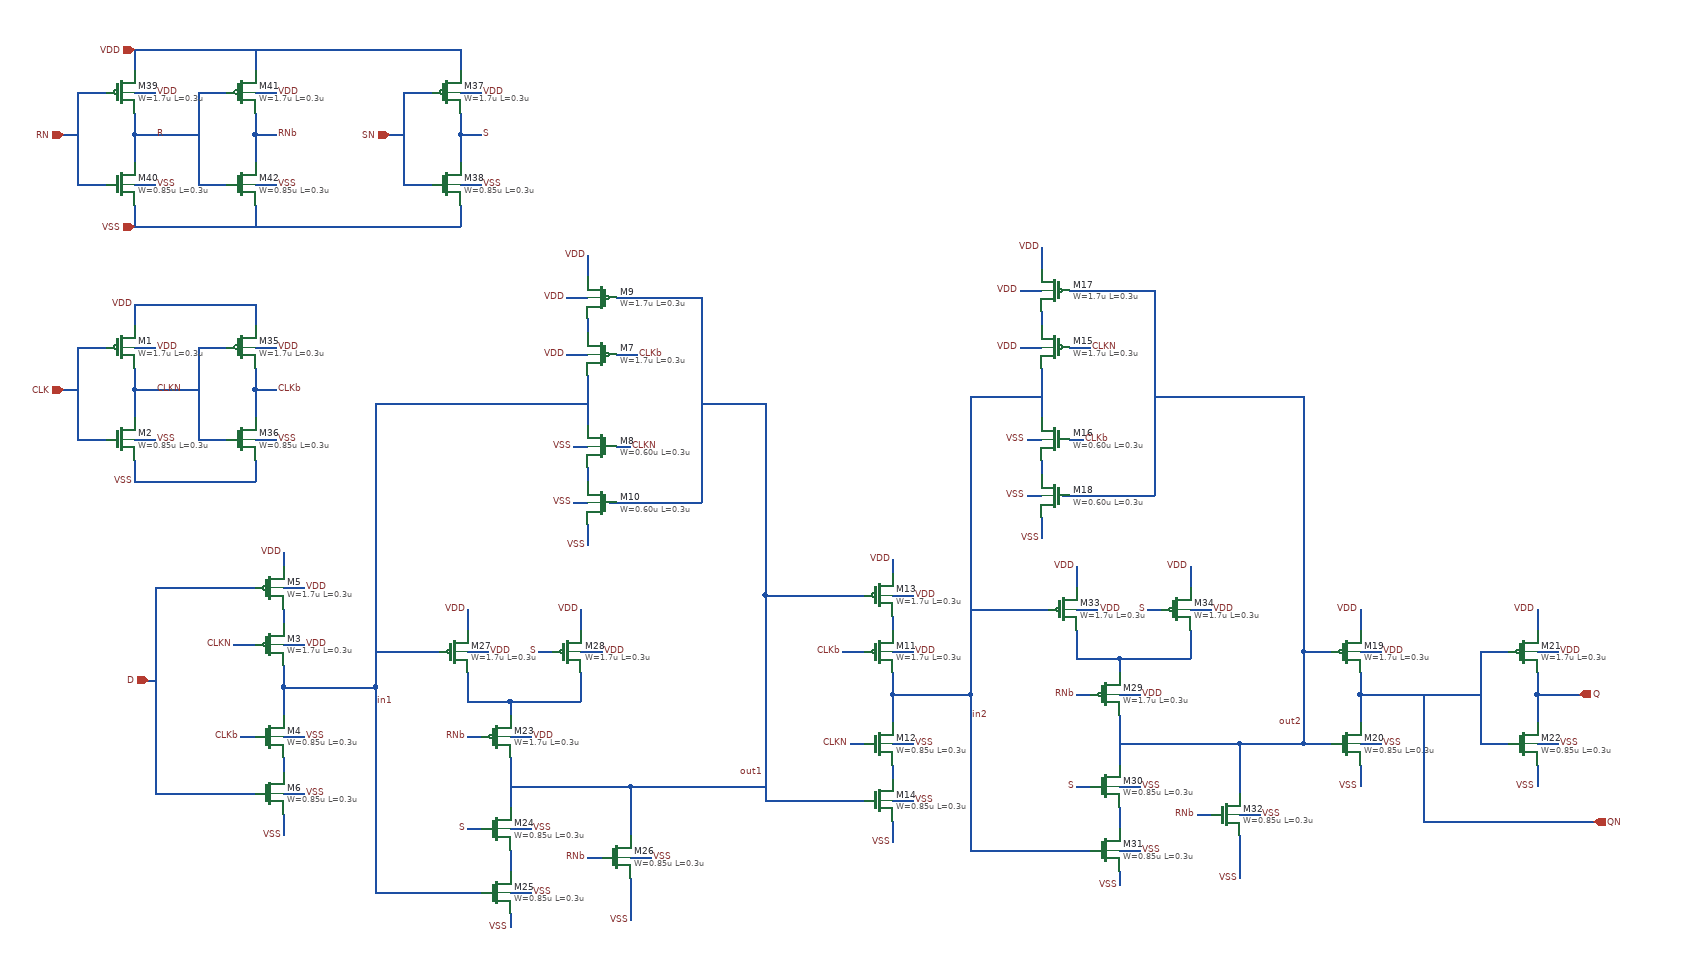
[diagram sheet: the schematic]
v {xschem version=3.4.6 file_version=1.2}
G {}
K {}
V {}
S {}
E {}
N 60 -780 60 -750 { lab=VDD}
N 60 -690 60 -660 { lab=CLKN}
N 60 -660 60 -620 { lab=CLKN}
N 60 -560 60 -530 { lab=VSS}
N 0 -720 20 -720 { lab=CLK}
N -20 -720 -20 -590 { lab=CLK}
N -40 -660 -20 -660 { lab=CLK}
N -20 -720 0 -720 { lab=CLK}
N -20 -590 20 -590 { lab=CLK}
N 60 -720 90 -720 { lab=VDD}
N 60 -590 90 -590 { lab=VSS}
N 270 -270 270 -240 { lab=in1}
N 270 -240 270 -200 { lab=in1}
N 270 -300 300 -300 { lab=VDD}
N 270 -170 300 -170 { lab=VSS}
N 210 -380 230 -380 { lab=D}
N 270 -380 300 -380 { lab=VDD}
N 270 -350 270 -330 { lab=#net1}
N 270 -60 270 -30 { lab=VSS}
N 270 -90 300 -90 { lab=VSS}
N 270 -140 270 -120 { lab=#net2}
N 270 -430 270 -400 { lab=#net3}
N 90 -90 230 -90 { lab=D}
N 90 -380 90 -90 { lab=D}
N 90 -380 210 -380 { lab=D}
N 80 -250 90 -250 { lab=D}
N 700 -470 700 -440 { lab=VSS}
N 700 -850 700 -820 { lab=#net4}
N 700 -760 700 -740 { lab=#net5}
N 700 -550 700 -530 { lab=#net6}
N 700 -680 700 -610 { lab=in1}
N 670 -790 700 -790 { lab=VDD}
N 670 -710 700 -710 { lab=VDD}
N 680 -500 700 -500 { lab=VSS}
N 680 -580 700 -580 { lab=VSS}
N 730 -500 860 -500 { lab=out1}
N 740 -790 860 -790 { lab=out1}
N 860 -790 860 -500 { lab=out1}
N 740 -710 770 -710 { lab=CLKb}
N 740 -580 760 -580 { lab=CLKN}
N 1130 -260 1130 -230 { lab=in2}
N 1130 -230 1130 -190 { lab=in2}
N 1130 -290 1160 -290 { lab=VDD}
N 1130 -160 1160 -160 { lab=VSS}
N 1130 -230 1160 -230 { lab=in2}
N 1070 -370 1090 -370 { lab=out1}
N 1130 -370 1160 -370 { lab=VDD}
N 1130 -340 1130 -320 { lab=#net7}
N 1130 -50 1130 -20 { lab=VSS}
N 1130 -80 1160 -80 { lab=VSS}
N 1130 -130 1130 -110 { lab=#net8}
N 1130 -420 1130 -390 { lab=#net9}
N 950 -80 1090 -80 { lab=out1}
N 950 -370 1070 -370 { lab=out1}
N 1340 -480 1340 -450 { lab=VSS}
N 1340 -860 1340 -830 { lab=#net10}
N 1340 -770 1340 -750 { lab=#net11}
N 1340 -560 1340 -540 { lab=#net12}
N 1340 -690 1340 -620 { lab=in2}
N 1310 -800 1340 -800 { lab=VDD}
N 1310 -720 1340 -720 { lab=VDD}
N 1320 -510 1340 -510 { lab=VSS}
N 1320 -590 1340 -590 { lab=VSS}
N 1370 -510 1500 -510 { lab=out2}
N 1380 -800 1500 -800 { lab=out2}
N 1500 -800 1500 -510 { lab=out2}
N 1380 -720 1410 -720 { lab=CLKN}
N 1380 -590 1400 -590 { lab=CLKb}
N 1160 -230 1240 -230 { lab=in2}
N 1240 -650 1240 -230 { lab=in2}
N 1240 -650 1340 -650 { lab=in2}
N 1790 -350 1790 -320 { lab=#net13}
N 1790 -260 1790 -230 { lab=QN}
N 1790 -230 1790 -190 { lab=QN}
N 1790 -130 1790 -100 { lab=VSS}
N 1730 -290 1750 -290 { lab=out2}
N 1710 -290 1710 -160 { lab=out2}
N 1710 -290 1730 -290 { lab=out2}
N 1710 -160 1750 -160 { lab=out2}
N 1790 -290 1820 -290 { lab=VDD}
N 1790 -160 1820 -160 { lab=VSS}
N 2040 -350 2040 -320 { lab=#net14}
N 2040 -260 2040 -230 { lab=Q}
N 2040 -230 2040 -190 { lab=Q}
N 2040 -130 2040 -100 { lab=VSS}
N 1980 -290 2000 -290 { lab=QN}
N 1960 -290 1960 -160 { lab=QN}
N 1960 -290 1980 -290 { lab=QN}
N 1960 -160 2000 -160 { lab=QN}
N 2040 -290 2070 -290 { lab=VDD}
N 2040 -160 2070 -160 { lab=VSS}
N 1790 -230 1960 -230 { lab=QN}
N 2040 -230 2100 -230 { lab=Q}
N 1880 -230 1880 -50 { lab=QN}
N 1880 -50 2120 -50 { lab=QN}
N 210 -170 230 -170 { lab=CLKb}
N 1070 -160 1090 -160 { lab=CLKN}
N 200 -300 230 -300 { lab=CLKN}
N 1060 -290 1090 -290 { lab=CLKb}
N 590 -140 590 -110 { lab=out1}
N 590 -110 590 -70 { lab=out1}
N 530 -170 550 -170 { lab=RNb}
N 590 -170 620 -170 { lab=VDD}
N 590 -40 620 -40 { lab=VSS}
N 590 50 620 50 { lab=VSS}
N 590 -10 590 20 { lab=#net15}
N 590 80 590 100 { lab=VSS}
N 760 30 760 90 { lab=VSS}
N 760 -100 760 -30 { lab=out1}
N 590 -100 760 -100 { lab=out1}
N 530 -290 560 -290 { lab=VDD}
N 630 -290 650 -290 { lab=S}
N 690 -290 720 -290 { lab=VDD}
N 530 -260 530 -220 { lab=#net16}
N 530 -220 590 -220 { lab=#net16}
N 590 -220 690 -220 { lab=#net16}
N 690 -260 690 -220 { lab=#net16}
N 590 -220 590 -200 { lab=#net16}
N 530 -350 530 -320 { lab=#net17}
N 690 -350 690 -320 { lab=#net18}
N 700 0 720 0 { lab=RNb}
N 760 0 790 0 { lab=VSS}
N 950 -370 950 -80 { lab=out1}
N 530 -40 550 -40 { lab=S}
N 1450 -200 1450 -170 { lab=out2}
N 1450 -170 1450 -130 { lab=out2}
N 1390 -230 1410 -230 { lab=RNb}
N 1450 -230 1480 -230 { lab=VDD}
N 1450 -100 1480 -100 { lab=VSS}
N 1450 -10 1480 -10 { lab=VSS}
N 1450 -70 1450 -40 { lab=#net19}
N 1450 20 1450 40 { lab=VSS}
N 1620 -30 1620 30 { lab=VSS}
N 1450 -160 1620 -160 { lab=out2}
N 1390 -350 1420 -350 { lab=VDD}
N 1490 -350 1510 -350 { lab=S}
N 1550 -350 1580 -350 { lab=VDD}
N 1390 -320 1390 -280 { lab=#net20}
N 1390 -280 1450 -280 { lab=#net20}
N 1450 -280 1550 -280 { lab=#net20}
N 1550 -320 1550 -280 { lab=#net20}
N 1450 -280 1450 -260 { lab=#net20}
N 1390 -410 1390 -380 { lab=#net21}
N 1550 -410 1550 -380 { lab=#net22}
N 1560 -60 1580 -60 { lab=RNb}
N 1620 -60 1650 -60 { lab=VSS}
N 1390 -100 1410 -100 { lab=S}
N 520 -1140 520 -1110 { lab=VDD}
N 520 -1050 520 -1020 { lab=S}
N 520 -1020 520 -980 { lab=S}
N 520 -920 520 -890 { lab=VSS}
N 460 -1080 480 -1080 { lab=SN}
N 440 -1080 440 -950 { lab=SN}
N 420 -1020 440 -1020 { lab=SN}
N 440 -1080 460 -1080 { lab=SN}
N 440 -950 480 -950 { lab=SN}
N 520 -1080 550 -1080 { lab=VDD}
N 520 -950 550 -950 { lab=VSS}
N 520 -1020 550 -1020 { lab=S}
N 1620 -160 1620 -90 {lab=out2}
N 400 -640 400 -240 {lab=in1}
N 230 -780 230 -750 { lab=VDD}
N 230 -690 230 -660 { lab=CLKb}
N 230 -660 230 -620 { lab=CLKb}
N 230 -560 230 -530 { lab=VSS}
N 170 -720 190 -720 { lab=CLKN}
N 150 -720 150 -590 { lab=CLKN}
N 150 -720 170 -720 { lab=CLKN}
N 150 -590 190 -590 { lab=CLKN}
N 230 -720 260 -720 { lab=VDD}
N 230 -590 260 -590 { lab=VSS}
N 230 -660 260 -660 { lab=CLKb}
N 60 -660 150 -660 {lab=CLKN}
N 270 -240 400 -240 {lab=in1}
N 400 -640 700 -640 {lab=in1}
N 760 -100 950 -100 {lab=out1}
N 860 -640 950 -640 {lab=out1}
N 950 -640 950 -370 {lab=out1}
N 400 -240 400 50 {lab=in1}
N 400 50 550 50 {lab=in1}
N 1710 -650 1710 -290 {lab=out2}
N 1500 -650 1710 -650 {lab=out2}
N 1620 -160 1710 -160 {lab=out2}
N 1240 -350 1350 -350 {lab=in2}
N 1240 -230 1240 -10 {lab=in2}
N 1240 -10 1410 -10 {lab=in2}
N 400 -290 490 -290 {lab=in1}
N 60 -1140 60 -1110 { lab=VDD}
N 60 -1050 60 -1020 { lab=R}
N 60 -1020 60 -980 { lab=R}
N 60 -920 60 -890 { lab=VSS}
N 0 -1080 20 -1080 { lab=RN}
N -20 -1080 -20 -950 { lab=RN}
N -40 -1020 -20 -1020 { lab=RN}
N -20 -1080 0 -1080 { lab=RN}
N -20 -950 20 -950 { lab=RN}
N 60 -1080 90 -1080 { lab=VDD}
N 60 -950 90 -950 { lab=VSS}
N 230 -1140 230 -1110 { lab=VDD}
N 230 -1050 230 -1020 { lab=RNb}
N 230 -1020 230 -980 { lab=RNb}
N 230 -920 230 -890 { lab=VSS}
N 170 -1080 190 -1080 { lab=R}
N 150 -1080 150 -950 { lab=R}
N 150 -1080 170 -1080 { lab=R}
N 150 -950 190 -950 { lab=R}
N 230 -1080 260 -1080 { lab=VDD}
N 230 -950 260 -950 { lab=VSS}
N 230 -1020 260 -1020 { lab=RNb}
N 60 -1020 150 -1020 {lab=R}
N 60 -1140 520 -1140 {lab=VDD}
N 60 -890 520 -890 {lab=VSS}
N 60 -780 230 -780 {lab=VDD}
N 60 -530 230 -530 {lab=VSS}
C {symbols/pfet_03v3.sym} 40 -720 0 0 {name=M1 L=0.3u W=1.7u m=1 nf=1 ad="'int((nf+1)/2) * W/nf * 0.18u'" pd="'2*int((nf+1)/2) * (W/nf + 0.18u)'" as="'int((nf+2)/2) * W/nf * 0.18u'" ps="'2*int((nf+2)/2) * (W/nf + 0.18u)'" nrd="'0.18u / W'" nrs="'0.18u / W'" sa=0 sb=0 sd=0 model=pfet_03v3 spiceprefix=X}
C {symbols/nfet_03v3.sym} 40 -590 0 0 {name=M2 L=0.3u W=0.85u m=1 nf=1 ad="'int((nf+1)/2) * W/nf * 0.18u'" pd="'2*int((nf+1)/2) * (W/nf + 0.18u)'" as="'int((nf+2)/2) * W/nf * 0.18u'" ps="'2*int((nf+2)/2) * (W/nf + 0.18u)'" nrd="'0.18u / W'" nrs="'0.18u / W'" sa=0 sb=0 sd=0 model=nfet_03v3 spiceprefix=X}
C {lab_wire.sym} 90 -720 2 0 {name=l2 sig_type=std_logic lab=VDD
}
C {lab_wire.sym} 90 -590 2 0 {name=l4 sig_type=std_logic lab=VSS
}
C {lab_wire.sym} 90 -660 2 0 {name=l5 sig_type=std_logic lab=CLKN}
C {symbols/pfet_03v3.sym} 250 -300 0 0 {name=M3 L=0.3u W=1.7u m=1 nf=1 ad="'int((nf+1)/2) * W/nf * 0.18u'" pd="'2*int((nf+1)/2) * (W/nf + 0.18u)'" as="'int((nf+2)/2) * W/nf * 0.18u'" ps="'2*int((nf+2)/2) * (W/nf + 0.18u)'" nrd="'0.18u / W'" nrs="'0.18u / W'" sa=0 sb=0 sd=0 model=pfet_03v3 spiceprefix=X}
C {symbols/nfet_03v3.sym} 250 -170 0 0 {name=M4 L=0.3u W=0.85u m=1 nf=1 ad="'int((nf+1)/2) * W/nf * 0.18u'" pd="'2*int((nf+1)/2) * (W/nf + 0.18u)'" as="'int((nf+2)/2) * W/nf * 0.18u'" ps="'2*int((nf+2)/2) * (W/nf + 0.18u)'" nrd="'0.18u / W'" nrs="'0.18u / W'" sa=0 sb=0 sd=0 model=nfet_03v3 spiceprefix=X}
C {lab_wire.sym} 300 -300 2 0 {name=l6 sig_type=std_logic lab=VDD
}
C {lab_wire.sym} 300 -170 2 0 {name=l7 sig_type=std_logic lab=VSS
}
C {symbols/pfet_03v3.sym} 250 -380 0 0 {name=M5 L=0.3u W=1.7u m=1 nf=1 ad="'int((nf+1)/2) * W/nf * 0.18u'" pd="'2*int((nf+1)/2) * (W/nf + 0.18u)'" as="'int((nf+2)/2) * W/nf * 0.18u'" ps="'2*int((nf+2)/2) * (W/nf + 0.18u)'" nrd="'0.18u / W'" nrs="'0.18u / W'" sa=0 sb=0 sd=0 model=pfet_03v3 spiceprefix=X}
C {lab_wire.sym} 300 -380 2 0 {name=l9 sig_type=std_logic lab=VDD
}
C {symbols/nfet_03v3.sym} 250 -90 0 0 {name=M6 L=0.3u W=0.85u m=1 nf=1 ad="'int((nf+1)/2) * W/nf * 0.18u'" pd="'2*int((nf+1)/2) * (W/nf + 0.18u)'" as="'int((nf+2)/2) * W/nf * 0.18u'" ps="'2*int((nf+2)/2) * (W/nf + 0.18u)'" nrd="'0.18u / W'" nrs="'0.18u / W'" sa=0 sb=0 sd=0 model=nfet_03v3 spiceprefix=X}
C {lab_wire.sym} 300 -90 2 0 {name=l10 sig_type=std_logic lab=VSS
}
C {lab_wire.sym} 200 -300 0 0 {name=l13 sig_type=std_logic lab=CLKN}
C {lab_wire.sym} 210 -170 0 0 {name=l14 sig_type=std_logic lab=CLKb}
C {symbols/pfet_03v3.sym} 720 -710 0 1 {name=M7 L=0.3u W=1.7u m=1 nf=1 ad="'int((nf+1)/2) * W/nf * 0.18u'" pd="'2*int((nf+1)/2) * (W/nf + 0.18u)'" as="'int((nf+2)/2) * W/nf * 0.18u'" ps="'2*int((nf+2)/2) * (W/nf + 0.18u)'" nrd="'0.18u / W'" nrs="'0.18u / W'" sa=0 sb=0 sd=0 model=pfet_03v3 spiceprefix=X}
C {symbols/nfet_03v3.sym} 720 -580 0 1 {name=M8 L=0.3u W=0.60u m=1 nf=1 ad="'int((nf+1)/2) * W/nf * 0.18u'" pd="'2*int((nf+1)/2) * (W/nf + 0.18u)'" as="'int((nf+2)/2) * W/nf * 0.18u'" ps="'2*int((nf+2)/2) * (W/nf + 0.18u)'" nrd="'0.18u / W'" nrs="'0.18u / W'" sa=0 sb=0 sd=0 model=nfet_03v3 spiceprefix=X}
C {lab_wire.sym} 670 -710 2 1 {name=l15 sig_type=std_logic lab=VDD
}
C {lab_wire.sym} 680 -580 2 1 {name=l16 sig_type=std_logic lab=VSS
}
C {lab_wire.sym} 760 -580 0 1 {name=l17 sig_type=std_logic lab=CLKN}
C {symbols/pfet_03v3.sym} 720 -790 0 1 {name=M9 L=0.3u W=1.7u m=1 nf=1 ad="'int((nf+1)/2) * W/nf * 0.18u'" pd="'2*int((nf+1)/2) * (W/nf + 0.18u)'" as="'int((nf+2)/2) * W/nf * 0.18u'" ps="'2*int((nf+2)/2) * (W/nf + 0.18u)'" nrd="'0.18u / W'" nrs="'0.18u / W'" sa=0 sb=0 sd=0 model=pfet_03v3 spiceprefix=X}
C {lab_wire.sym} 670 -790 2 1 {name=l18 sig_type=std_logic lab=VDD
}
C {symbols/nfet_03v3.sym} 720 -500 0 1 {name=M10 L=0.3u W=0.60u m=1 nf=1 ad="'int((nf+1)/2) * W/nf * 0.18u'" pd="'2*int((nf+1)/2) * (W/nf + 0.18u)'" as="'int((nf+2)/2) * W/nf * 0.18u'" ps="'2*int((nf+2)/2) * (W/nf + 0.18u)'" nrd="'0.18u / W'" nrs="'0.18u / W'" sa=0 sb=0 sd=0 model=nfet_03v3 spiceprefix=X}
C {lab_wire.sym} 680 -500 2 1 {name=l19 sig_type=std_logic lab=VSS
}
C {lab_wire.sym} 770 -710 0 1 {name=l22 sig_type=std_logic lab=CLKb}
C {symbols/pfet_03v3.sym} 1110 -290 0 0 {name=M11 L=0.3u W=1.7u m=1 nf=1 ad="'int((nf+1)/2) * W/nf * 0.18u'" pd="'2*int((nf+1)/2) * (W/nf + 0.18u)'" as="'int((nf+2)/2) * W/nf * 0.18u'" ps="'2*int((nf+2)/2) * (W/nf + 0.18u)'" nrd="'0.18u / W'" nrs="'0.18u / W'" sa=0 sb=0 sd=0 model=pfet_03v3 spiceprefix=X}
C {symbols/nfet_03v3.sym} 1110 -160 0 0 {name=M12 L=0.3u W=0.85u m=1 nf=1 ad="'int((nf+1)/2) * W/nf * 0.18u'" pd="'2*int((nf+1)/2) * (W/nf + 0.18u)'" as="'int((nf+2)/2) * W/nf * 0.18u'" ps="'2*int((nf+2)/2) * (W/nf + 0.18u)'" nrd="'0.18u / W'" nrs="'0.18u / W'" sa=0 sb=0 sd=0 model=nfet_03v3 spiceprefix=X}
C {lab_wire.sym} 1160 -290 2 0 {name=l26 sig_type=std_logic lab=VDD
}
C {lab_wire.sym} 1160 -160 2 0 {name=l27 sig_type=std_logic lab=VSS
}
C {symbols/pfet_03v3.sym} 1110 -370 0 0 {name=M13 L=0.3u W=1.7u m=1 nf=1 ad="'int((nf+1)/2) * W/nf * 0.18u'" pd="'2*int((nf+1)/2) * (W/nf + 0.18u)'" as="'int((nf+2)/2) * W/nf * 0.18u'" ps="'2*int((nf+2)/2) * (W/nf + 0.18u)'" nrd="'0.18u / W'" nrs="'0.18u / W'" sa=0 sb=0 sd=0 model=pfet_03v3 spiceprefix=X}
C {lab_wire.sym} 1160 -370 2 0 {name=l28 sig_type=std_logic lab=VDD
}
C {symbols/nfet_03v3.sym} 1110 -80 0 0 {name=M14 L=0.3u W=0.85u m=1 nf=1 ad="'int((nf+1)/2) * W/nf * 0.18u'" pd="'2*int((nf+1)/2) * (W/nf + 0.18u)'" as="'int((nf+2)/2) * W/nf * 0.18u'" ps="'2*int((nf+2)/2) * (W/nf + 0.18u)'" nrd="'0.18u / W'" nrs="'0.18u / W'" sa=0 sb=0 sd=0 model=nfet_03v3 spiceprefix=X}
C {lab_wire.sym} 1160 -80 2 0 {name=l29 sig_type=std_logic lab=VSS
}
C {lab_wire.sym} 1060 -290 0 0 {name=l32 sig_type=std_logic lab=CLKb}
C {lab_wire.sym} 1070 -160 0 0 {name=l33 sig_type=std_logic lab=CLKN}
C {symbols/pfet_03v3.sym} 1360 -720 0 1 {name=M15 L=0.3u W=1.7u m=1 nf=1 ad="'int((nf+1)/2) * W/nf * 0.18u'" pd="'2*int((nf+1)/2) * (W/nf + 0.18u)'" as="'int((nf+2)/2) * W/nf * 0.18u'" ps="'2*int((nf+2)/2) * (W/nf + 0.18u)'" nrd="'0.18u / W'" nrs="'0.18u / W'" sa=0 sb=0 sd=0 model=pfet_03v3 spiceprefix=X}
C {symbols/nfet_03v3.sym} 1360 -590 0 1 {name=M16 L=0.3u W=0.60u m=1 nf=1 ad="'int((nf+1)/2) * W/nf * 0.18u'" pd="'2*int((nf+1)/2) * (W/nf + 0.18u)'" as="'int((nf+2)/2) * W/nf * 0.18u'" ps="'2*int((nf+2)/2) * (W/nf + 0.18u)'" nrd="'0.18u / W'" nrs="'0.18u / W'" sa=0 sb=0 sd=0 model=nfet_03v3 spiceprefix=X}
C {lab_wire.sym} 1310 -720 2 1 {name=l34 sig_type=std_logic lab=VDD
}
C {lab_wire.sym} 1320 -590 2 1 {name=l35 sig_type=std_logic lab=VSS
}
C {lab_wire.sym} 1400 -590 0 1 {name=l36 sig_type=std_logic lab=CLKb}
C {symbols/pfet_03v3.sym} 1360 -800 0 1 {name=M17 L=0.3u W=1.7u m=1 nf=1 ad="'int((nf+1)/2) * W/nf * 0.18u'" pd="'2*int((nf+1)/2) * (W/nf + 0.18u)'" as="'int((nf+2)/2) * W/nf * 0.18u'" ps="'2*int((nf+2)/2) * (W/nf + 0.18u)'" nrd="'0.18u / W'" nrs="'0.18u / W'" sa=0 sb=0 sd=0 model=pfet_03v3 spiceprefix=X}
C {lab_wire.sym} 1310 -800 2 1 {name=l37 sig_type=std_logic lab=VDD
}
C {symbols/nfet_03v3.sym} 1360 -510 0 1 {name=M18 L=0.3u W=0.60u m=1 nf=1 ad="'int((nf+1)/2) * W/nf * 0.18u'" pd="'2*int((nf+1)/2) * (W/nf + 0.18u)'" as="'int((nf+2)/2) * W/nf * 0.18u'" ps="'2*int((nf+2)/2) * (W/nf + 0.18u)'" nrd="'0.18u / W'" nrs="'0.18u / W'" sa=0 sb=0 sd=0 model=nfet_03v3 spiceprefix=X}
C {lab_wire.sym} 1320 -510 2 1 {name=l38 sig_type=std_logic lab=VSS
}
C {lab_wire.sym} 1410 -720 0 1 {name=l41 sig_type=std_logic lab=CLKN}
C {symbols/pfet_03v3.sym} 1770 -290 0 0 {name=M19 L=0.3u W=1.7u m=1 nf=1 ad="'int((nf+1)/2) * W/nf * 0.18u'" pd="'2*int((nf+1)/2) * (W/nf + 0.18u)'" as="'int((nf+2)/2) * W/nf * 0.18u'" ps="'2*int((nf+2)/2) * (W/nf + 0.18u)'" nrd="'0.18u / W'" nrs="'0.18u / W'" sa=0 sb=0 sd=0 model=pfet_03v3 spiceprefix=X}
C {symbols/nfet_03v3.sym} 1770 -160 0 0 {name=M20 L=0.3u W=0.85u m=1 nf=1 ad="'int((nf+1)/2) * W/nf * 0.18u'" pd="'2*int((nf+1)/2) * (W/nf + 0.18u)'" as="'int((nf+2)/2) * W/nf * 0.18u'" ps="'2*int((nf+2)/2) * (W/nf + 0.18u)'" nrd="'0.18u / W'" nrs="'0.18u / W'" sa=0 sb=0 sd=0 model=nfet_03v3 spiceprefix=X}
C {lab_wire.sym} 1820 -290 2 0 {name=l48 sig_type=std_logic lab=VDD
}
C {lab_wire.sym} 1820 -160 2 0 {name=l49 sig_type=std_logic lab=VSS
}
C {symbols/pfet_03v3.sym} 2020 -290 0 0 {name=M21 L=0.3u W=1.7u m=1 nf=1 ad="'int((nf+1)/2) * W/nf * 0.18u'" pd="'2*int((nf+1)/2) * (W/nf + 0.18u)'" as="'int((nf+2)/2) * W/nf * 0.18u'" ps="'2*int((nf+2)/2) * (W/nf + 0.18u)'" nrd="'0.18u / W'" nrs="'0.18u / W'" sa=0 sb=0 sd=0 model=pfet_03v3 spiceprefix=X}
C {symbols/nfet_03v3.sym} 2020 -160 0 0 {name=M22 L=0.3u W=0.85u m=1 nf=1 ad="'int((nf+1)/2) * W/nf * 0.18u'" pd="'2*int((nf+1)/2) * (W/nf + 0.18u)'" as="'int((nf+2)/2) * W/nf * 0.18u'" ps="'2*int((nf+2)/2) * (W/nf + 0.18u)'" nrd="'0.18u / W'" nrs="'0.18u / W'" sa=0 sb=0 sd=0 model=nfet_03v3 spiceprefix=X}
C {lab_wire.sym} 2070 -290 2 0 {name=l52 sig_type=std_logic lab=VDD
}
C {lab_wire.sym} 2070 -160 2 0 {name=l53 sig_type=std_logic lab=VSS
}
C {symbols/pfet_03v3.sym} 570 -170 0 0 {name=M23 L=0.3u W=1.7u m=1 nf=1 ad="'int((nf+1)/2) * W/nf * 0.18u'" pd="'2*int((nf+1)/2) * (W/nf + 0.18u)'" as="'int((nf+2)/2) * W/nf * 0.18u'" ps="'2*int((nf+2)/2) * (W/nf + 0.18u)'" nrd="'0.18u / W'" nrs="'0.18u / W'" sa=0 sb=0 sd=0 model=pfet_03v3 spiceprefix=X}
C {symbols/nfet_03v3.sym} 570 -40 0 0 {name=M24 L=0.3u W=0.85u m=1 nf=1 ad="'int((nf+1)/2) * W/nf * 0.18u'" pd="'2*int((nf+1)/2) * (W/nf + 0.18u)'" as="'int((nf+2)/2) * W/nf * 0.18u'" ps="'2*int((nf+2)/2) * (W/nf + 0.18u)'" nrd="'0.18u / W'" nrs="'0.18u / W'" sa=0 sb=0 sd=0 model=nfet_03v3 spiceprefix=X}
C {lab_wire.sym} 620 -170 2 0 {name=l54 sig_type=std_logic lab=VDD
}
C {lab_wire.sym} 620 -40 2 0 {name=l55 sig_type=std_logic lab=VSS
}
C {symbols/nfet_03v3.sym} 570 50 0 0 {name=M25 L=0.3u W=0.85u m=1 nf=1 ad="'int((nf+1)/2) * W/nf * 0.18u'" pd="'2*int((nf+1)/2) * (W/nf + 0.18u)'" as="'int((nf+2)/2) * W/nf * 0.18u'" ps="'2*int((nf+2)/2) * (W/nf + 0.18u)'" nrd="'0.18u / W'" nrs="'0.18u / W'" sa=0 sb=0 sd=0 model=nfet_03v3 spiceprefix=X}
C {lab_wire.sym} 620 50 2 0 {name=l56 sig_type=std_logic lab=VSS
}
C {symbols/nfet_03v3.sym} 740 0 0 0 {name=M26 L=0.3u W=0.85u m=1 nf=1 ad="'int((nf+1)/2) * W/nf * 0.18u'" pd="'2*int((nf+1)/2) * (W/nf + 0.18u)'" as="'int((nf+2)/2) * W/nf * 0.18u'" ps="'2*int((nf+2)/2) * (W/nf + 0.18u)'" nrd="'0.18u / W'" nrs="'0.18u / W'" sa=0 sb=0 sd=0 model=nfet_03v3 spiceprefix=X}
C {symbols/pfet_03v3.sym} 510 -290 0 0 {name=M27 L=0.3u W=1.7u m=1 nf=1 ad="'int((nf+1)/2) * W/nf * 0.18u'" pd="'2*int((nf+1)/2) * (W/nf + 0.18u)'" as="'int((nf+2)/2) * W/nf * 0.18u'" ps="'2*int((nf+2)/2) * (W/nf + 0.18u)'" nrd="'0.18u / W'" nrs="'0.18u / W'" sa=0 sb=0 sd=0 model=pfet_03v3 spiceprefix=X}
C {lab_wire.sym} 560 -290 2 0 {name=l59 sig_type=std_logic lab=VDD
}
C {symbols/pfet_03v3.sym} 670 -290 0 0 {name=M28 L=0.3u W=1.7u m=1 nf=1 ad="'int((nf+1)/2) * W/nf * 0.18u'" pd="'2*int((nf+1)/2) * (W/nf + 0.18u)'" as="'int((nf+2)/2) * W/nf * 0.18u'" ps="'2*int((nf+2)/2) * (W/nf + 0.18u)'" nrd="'0.18u / W'" nrs="'0.18u / W'" sa=0 sb=0 sd=0 model=pfet_03v3 spiceprefix=X}
C {lab_wire.sym} 720 -290 2 0 {name=l60 sig_type=std_logic lab=VDD
}
C {lab_wire.sym} 700 0 0 0 {name=l63 sig_type=std_logic lab=RNb}
C {lab_wire.sym} 790 0 2 0 {name=l65 sig_type=std_logic lab=VSS
}
C {lab_wire.sym} 400 -220 2 0 {name=l8 sig_type=std_logic lab=in1
}
C {lab_wire.sym} 950 -120 0 0 {name=l23 sig_type=std_logic lab=out1
}
C {lab_wire.sym} 630 -290 0 0 {name=l67 sig_type=std_logic lab=S}
C {lab_wire.sym} 1240 -200 2 0 {name=l42 sig_type=std_logic lab=in2
}
C {lab_wire.sym} 1710 -190 0 0 {name=l43 sig_type=std_logic lab=out2
}
C {symbols/pfet_03v3.sym} 1430 -230 0 0 {name=M29 L=0.3u W=1.7u m=1 nf=1 ad="'int((nf+1)/2) * W/nf * 0.18u'" pd="'2*int((nf+1)/2) * (W/nf + 0.18u)'" as="'int((nf+2)/2) * W/nf * 0.18u'" ps="'2*int((nf+2)/2) * (W/nf + 0.18u)'" nrd="'0.18u / W'" nrs="'0.18u / W'" sa=0 sb=0 sd=0 model=pfet_03v3 spiceprefix=X}
C {symbols/nfet_03v3.sym} 1430 -100 0 0 {name=M30 L=0.3u W=0.85u m=1 nf=1 ad="'int((nf+1)/2) * W/nf * 0.18u'" pd="'2*int((nf+1)/2) * (W/nf + 0.18u)'" as="'int((nf+2)/2) * W/nf * 0.18u'" ps="'2*int((nf+2)/2) * (W/nf + 0.18u)'" nrd="'0.18u / W'" nrs="'0.18u / W'" sa=0 sb=0 sd=0 model=nfet_03v3 spiceprefix=X}
C {lab_wire.sym} 1480 -230 2 0 {name=l44 sig_type=std_logic lab=VDD
}
C {lab_wire.sym} 1480 -100 2 0 {name=l45 sig_type=std_logic lab=VSS
}
C {symbols/nfet_03v3.sym} 1430 -10 0 0 {name=M31 L=0.3u W=0.85u m=1 nf=1 ad="'int((nf+1)/2) * W/nf * 0.18u'" pd="'2*int((nf+1)/2) * (W/nf + 0.18u)'" as="'int((nf+2)/2) * W/nf * 0.18u'" ps="'2*int((nf+2)/2) * (W/nf + 0.18u)'" nrd="'0.18u / W'" nrs="'0.18u / W'" sa=0 sb=0 sd=0 model=nfet_03v3 spiceprefix=X}
C {lab_wire.sym} 1480 -10 2 0 {name=l69 sig_type=std_logic lab=VSS
}
C {symbols/nfet_03v3.sym} 1600 -60 0 0 {name=M32 L=0.3u W=0.85u m=1 nf=1 ad="'int((nf+1)/2) * W/nf * 0.18u'" pd="'2*int((nf+1)/2) * (W/nf + 0.18u)'" as="'int((nf+2)/2) * W/nf * 0.18u'" ps="'2*int((nf+2)/2) * (W/nf + 0.18u)'" nrd="'0.18u / W'" nrs="'0.18u / W'" sa=0 sb=0 sd=0 model=nfet_03v3 spiceprefix=X}
C {symbols/pfet_03v3.sym} 1370 -350 0 0 {name=M33 L=0.3u W=1.7u m=1 nf=1 ad="'int((nf+1)/2) * W/nf * 0.18u'" pd="'2*int((nf+1)/2) * (W/nf + 0.18u)'" as="'int((nf+2)/2) * W/nf * 0.18u'" ps="'2*int((nf+2)/2) * (W/nf + 0.18u)'" nrd="'0.18u / W'" nrs="'0.18u / W'" sa=0 sb=0 sd=0 model=pfet_03v3 spiceprefix=X}
C {lab_wire.sym} 1420 -350 2 0 {name=l72 sig_type=std_logic lab=VDD
}
C {symbols/pfet_03v3.sym} 1530 -350 0 0 {name=M34 L=0.3u W=1.7u m=1 nf=1 ad="'int((nf+1)/2) * W/nf * 0.18u'" pd="'2*int((nf+1)/2) * (W/nf + 0.18u)'" as="'int((nf+2)/2) * W/nf * 0.18u'" ps="'2*int((nf+2)/2) * (W/nf + 0.18u)'" nrd="'0.18u / W'" nrs="'0.18u / W'" sa=0 sb=0 sd=0 model=pfet_03v3 spiceprefix=X}
C {lab_wire.sym} 1580 -350 2 0 {name=l73 sig_type=std_logic lab=VDD
}
C {lab_wire.sym} 1560 -60 0 0 {name=l76 sig_type=std_logic lab=RNb}
C {lab_wire.sym} 1390 -230 0 0 {name=l77 sig_type=std_logic lab=RNb}
C {lab_wire.sym} 1650 -60 2 0 {name=l78 sig_type=std_logic lab=VSS
}
C {lab_wire.sym} 1390 -100 0 0 {name=l81 sig_type=std_logic lab=S}
C {lab_wire.sym} 1490 -350 0 0 {name=l82 sig_type=std_logic lab=S}
C {ipin.sym} 80 -250 0 0 {name=p1 lab=D}
C {ipin.sym} -40 -660 0 0 {name=p2 lab=CLK}
C {opin.sym} 2100 -230 0 0 {name=p3 lab=Q}
C {opin.sym} 2120 -50 0 0 {name=p4 lab=QN}
C {ipin.sym} 420 -1020 0 0 {name=p5 lab=SN}
C {ipin.sym} -40 -1020 0 0 {name=p6 lab=RN}
C {ipin.sym} 60 -1140 0 0 {name=p7 lab=VDD}
C {ipin.sym} 60 -890 0 0 {name=p8 lab=VSS}
C {symbols/pfet_03v3.sym} 500 -1080 0 0 {name=M37 L=0.3u W=1.7u m=1 nf=1 ad="'int((nf+1)/2) * W/nf * 0.18u'" pd="'2*int((nf+1)/2) * (W/nf + 0.18u)'" as="'int((nf+2)/2) * W/nf * 0.18u'" ps="'2*int((nf+2)/2) * (W/nf + 0.18u)'" nrd="'0.18u / W'" nrs="'0.18u / W'" sa=0 sb=0 sd=0 model=pfet_03v3 spiceprefix=X}
C {symbols/nfet_03v3.sym} 500 -950 0 0 {name=M38 L=0.3u W=0.85u m=1 nf=1 ad="'int((nf+1)/2) * W/nf * 0.18u'" pd="'2*int((nf+1)/2) * (W/nf + 0.18u)'" as="'int((nf+2)/2) * W/nf * 0.18u'" ps="'2*int((nf+2)/2) * (W/nf + 0.18u)'" nrd="'0.18u / W'" nrs="'0.18u / W'" sa=0 sb=0 sd=0 model=nfet_03v3 spiceprefix=X}
C {lab_wire.sym} 550 -1080 2 0 {name=l89 sig_type=std_logic lab=VDD
}
C {lab_wire.sym} 550 -950 2 0 {name=l90 sig_type=std_logic lab=VSS
}
C {lab_wire.sym} 550 -1020 2 0 {name=l91 sig_type=std_logic lab=S}
C {lab_wire.sym} 530 -170 0 0 {name=l92 sig_type=std_logic lab=RNb}
C {lab_wire.sym} 530 -40 0 0 {name=l93 sig_type=std_logic lab=S}
C {symbols/pfet_03v3.sym} 210 -720 0 0 {name=M35 L=0.3u W=1.7u m=1 nf=1 ad="'int((nf+1)/2) * W/nf * 0.18u'" pd="'2*int((nf+1)/2) * (W/nf + 0.18u)'" as="'int((nf+2)/2) * W/nf * 0.18u'" ps="'2*int((nf+2)/2) * (W/nf + 0.18u)'" nrd="'0.18u / W'" nrs="'0.18u / W'" sa=0 sb=0 sd=0 model=pfet_03v3 spiceprefix=X}
C {symbols/nfet_03v3.sym} 210 -590 0 0 {name=M36 L=0.3u W=0.85u m=1 nf=1 ad="'int((nf+1)/2) * W/nf * 0.18u'" pd="'2*int((nf+1)/2) * (W/nf + 0.18u)'" as="'int((nf+2)/2) * W/nf * 0.18u'" ps="'2*int((nf+2)/2) * (W/nf + 0.18u)'" nrd="'0.18u / W'" nrs="'0.18u / W'" sa=0 sb=0 sd=0 model=nfet_03v3 spiceprefix=X}
C {lab_wire.sym} 260 -720 2 0 {name=l84 sig_type=std_logic lab=VDD
}
C {lab_wire.sym} 260 -590 2 0 {name=l85 sig_type=std_logic lab=VSS
}
C {lab_wire.sym} 260 -660 2 0 {name=l86 sig_type=std_logic lab=CLKb}
C {symbols/pfet_03v3.sym} 40 -1080 0 0 {name=M39 L=0.3u W=1.7u m=1 nf=1 ad="'int((nf+1)/2) * W/nf * 0.18u'" pd="'2*int((nf+1)/2) * (W/nf + 0.18u)'" as="'int((nf+2)/2) * W/nf * 0.18u'" ps="'2*int((nf+2)/2) * (W/nf + 0.18u)'" nrd="'0.18u / W'" nrs="'0.18u / W'" sa=0 sb=0 sd=0 model=pfet_03v3 spiceprefix=X}
C {symbols/nfet_03v3.sym} 40 -950 0 0 {name=M40 L=0.3u W=0.85u m=1 nf=1 ad="'int((nf+1)/2) * W/nf * 0.18u'" pd="'2*int((nf+1)/2) * (W/nf + 0.18u)'" as="'int((nf+2)/2) * W/nf * 0.18u'" ps="'2*int((nf+2)/2) * (W/nf + 0.18u)'" nrd="'0.18u / W'" nrs="'0.18u / W'" sa=0 sb=0 sd=0 model=nfet_03v3 spiceprefix=X}
C {lab_wire.sym} 90 -1080 2 0 {name=l68 sig_type=std_logic lab=VDD
}
C {lab_wire.sym} 90 -950 2 0 {name=l79 sig_type=std_logic lab=VSS
}
C {lab_wire.sym} 90 -1020 2 0 {name=l80 sig_type=std_logic lab=R}
C {symbols/pfet_03v3.sym} 210 -1080 0 0 {name=M41 L=0.3u W=1.7u m=1 nf=1 ad="'int((nf+1)/2) * W/nf * 0.18u'" pd="'2*int((nf+1)/2) * (W/nf + 0.18u)'" as="'int((nf+2)/2) * W/nf * 0.18u'" ps="'2*int((nf+2)/2) * (W/nf + 0.18u)'" nrd="'0.18u / W'" nrs="'0.18u / W'" sa=0 sb=0 sd=0 model=pfet_03v3 spiceprefix=X}
C {symbols/nfet_03v3.sym} 210 -950 0 0 {name=M42 L=0.3u W=0.85u m=1 nf=1 ad="'int((nf+1)/2) * W/nf * 0.18u'" pd="'2*int((nf+1)/2) * (W/nf + 0.18u)'" as="'int((nf+2)/2) * W/nf * 0.18u'" ps="'2*int((nf+2)/2) * (W/nf + 0.18u)'" nrd="'0.18u / W'" nrs="'0.18u / W'" sa=0 sb=0 sd=0 model=nfet_03v3 spiceprefix=X}
C {lab_wire.sym} 260 -1080 2 0 {name=l95 sig_type=std_logic lab=VDD
}
C {lab_wire.sym} 260 -950 2 0 {name=l96 sig_type=std_logic lab=VSS
}
C {lab_wire.sym} 260 -1020 2 0 {name=l97 sig_type=std_logic lab=RNb}
C {lab_pin.sym} 60 -530 0 0 {name=p9 sig_type=std_logic lab=VSS}
C {lab_pin.sym} 60 -780 0 0 {name=p10 sig_type=std_logic lab=VDD}
C {lab_pin.sym} 270 -30 0 0 {name=p11 sig_type=std_logic lab=VSS}
C {lab_pin.sym} 590 100 0 0 {name=p12 sig_type=std_logic lab=VSS}
C {lab_pin.sym} 760 90 0 0 {name=p13 sig_type=std_logic lab=VSS}
C {lab_pin.sym} 1130 -20 0 0 {name=p14 sig_type=std_logic lab=VSS}
C {lab_pin.sym} 1450 40 0 0 {name=p15 sig_type=std_logic lab=VSS}
C {lab_pin.sym} 1620 30 0 0 {name=p16 sig_type=std_logic lab=VSS}
C {lab_pin.sym} 1790 -100 0 0 {name=p17 sig_type=std_logic lab=VSS}
C {lab_pin.sym} 2040 -100 0 0 {name=p18 sig_type=std_logic lab=VSS}
C {lab_pin.sym} 1340 -450 0 0 {name=p19 sig_type=std_logic lab=VSS}
C {lab_pin.sym} 700 -440 0 0 {name=p20 sig_type=std_logic lab=VSS}
C {lab_pin.sym} 270 -430 0 0 {name=p21 sig_type=std_logic lab=VDD}
C {lab_pin.sym} 530 -350 0 0 {name=p22 sig_type=std_logic lab=VDD}
C {lab_pin.sym} 690 -350 0 0 {name=p23 sig_type=std_logic lab=VDD}
C {lab_pin.sym} 1130 -420 0 0 {name=p24 sig_type=std_logic lab=VDD}
C {lab_pin.sym} 700 -850 0 0 {name=p25 sig_type=std_logic lab=VDD}
C {lab_pin.sym} 1340 -860 0 0 {name=p26 sig_type=std_logic lab=VDD}
C {lab_pin.sym} 1390 -410 0 0 {name=p27 sig_type=std_logic lab=VDD}
C {lab_pin.sym} 1550 -410 0 0 {name=p28 sig_type=std_logic lab=VDD}
C {lab_pin.sym} 1790 -350 0 0 {name=p29 sig_type=std_logic lab=VDD}
C {lab_pin.sym} 2040 -350 0 0 {name=p30 sig_type=std_logic lab=VDD}
